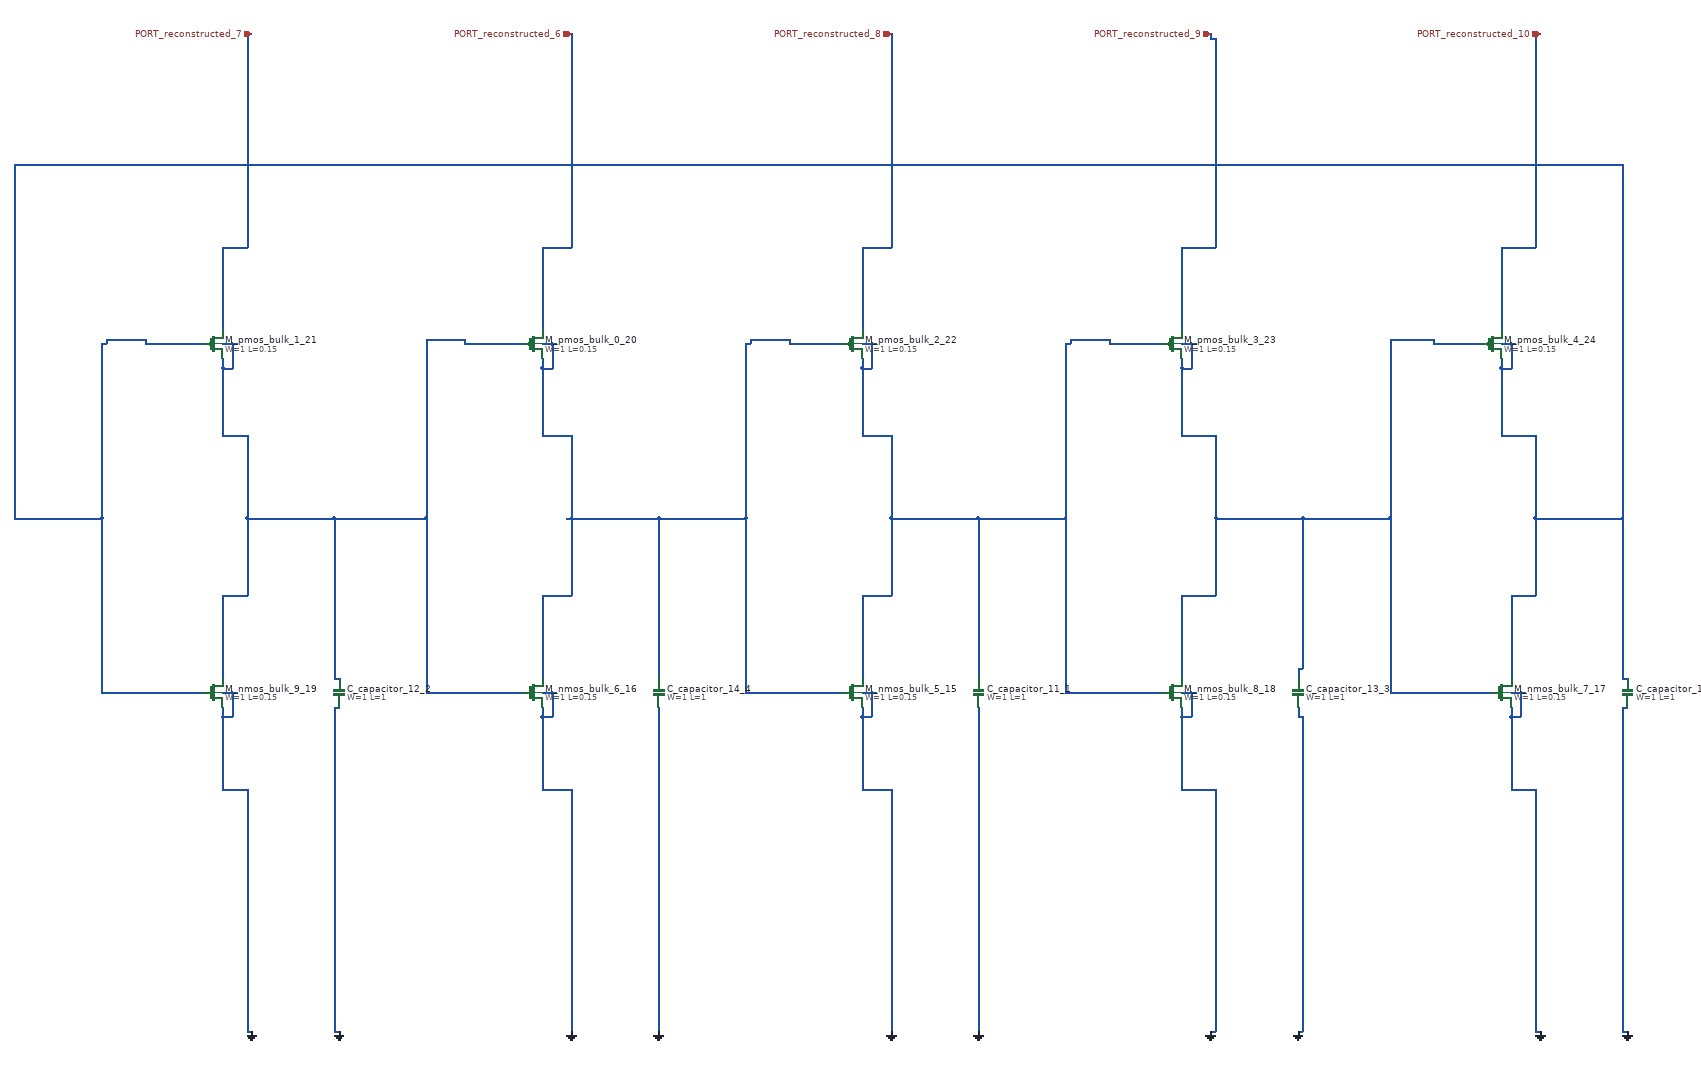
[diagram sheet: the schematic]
v {xschem version=3.4.8 file_version=1.2}
G {}
K {}
V {}
S {}
E {}
C {sky130_fd_pr/cap_mim_m3_1.sym} 3440 1560 0 0 {name="C_capacitor_10_0" model=cap_mim_m3_1 W=1 L=1 MF=1 spiceprefix=X}
C {sky130_fd_pr/cap_mim_m3_1.sym} 2100 1560 2 0 {name="C_capacitor_11_1" model=cap_mim_m3_1 W=1 L=1 MF=1 spiceprefix=X}
C {sky130_fd_pr/cap_mim_m3_1.sym} 780 1560 2 0 {name="C_capacitor_12_2" model=cap_mim_m3_1 W=1 L=1 MF=1 spiceprefix=X}
C {sky130_fd_pr/cap_mim_m3_1.sym} 2760 1560 2 0 {name="C_capacitor_13_3" model=cap_mim_m3_1 W=1 L=1 MF=1 spiceprefix=X}
C {sky130_fd_pr/cap_mim_m3_1.sym} 1440 1560 2 0 {name="C_capacitor_14_4" model=cap_mim_m3_1 W=1 L=1 MF=1 spiceprefix=X}
C {devices/gnd.sym} 3440 2260 0 0 {name="l_gnd_20_5" lab="GND"}
C {devices/gnd.sym} 2100 2260 0 0 {name="l_gnd_21_6" lab="GND"}
C {devices/gnd.sym} 2760 2260 0 0 {name="l_gnd_22_7" lab="GND"}
C {devices/gnd.sym} 1440 2260 0 0 {name="l_gnd_23_8" lab="GND"}
C {devices/gnd.sym} 780 2260 0 0 {name="l_gnd_24_9" lab="GND"}
C {devices/gnd.sym} 600 2260 0 0 {name="l_gnd_25_10" lab="GND"}
C {devices/gnd.sym} 3260 2260 0 0 {name="l_gnd_26_11" lab="GND"}
C {devices/gnd.sym} 2580 2260 0 0 {name="l_gnd_27_12" lab="GND"}
C {devices/gnd.sym} 1260 2260 0 0 {name="l_gnd_28_13" lab="GND"}
C {devices/gnd.sym} 1920 2260 0 0 {name="l_gnd_29_14" lab="GND"}
C {sky130_fd_pr/nfet_01v8.sym} 1840 1560 0 0 {name="M_nmos_bulk_5_15"
W=1
L=0.15
nf=1 
mult=1
ad="expr('int((@nf + 1)/2) * @W / @nf * 0.29')"
pd="expr('2*int((@nf + 1)/2) * (@W / @nf + 0.29)')"
as="expr('int((@nf + 2)/2) * @W / @nf * 0.29')"
ps="expr('2*int((@nf + 2)/2) * (@W / @nf + 0.29)')"
nrd="expr('0.29 / @W ')" nrs="expr('0.29 / @W ')"
sa=0 sb=0 sd=0
model=nfet_01v8
spiceprefix=X
}
C {sky130_fd_pr/nfet_01v8.sym} 1180 1560 0 0 {name="M_nmos_bulk_6_16"
W=1
L=0.15
nf=1 
mult=1
ad="expr('int((@nf + 1)/2) * @W / @nf * 0.29')"
pd="expr('2*int((@nf + 1)/2) * (@W / @nf + 0.29)')"
as="expr('int((@nf + 2)/2) * @W / @nf * 0.29')"
ps="expr('2*int((@nf + 2)/2) * (@W / @nf + 0.29)')"
nrd="expr('0.29 / @W ')" nrs="expr('0.29 / @W ')"
sa=0 sb=0 sd=0
model=nfet_01v8
spiceprefix=X
}
C {sky130_fd_pr/nfet_01v8.sym} 3180 1560 0 0 {name="M_nmos_bulk_7_17"
W=1
L=0.15
nf=1 
mult=1
ad="expr('int((@nf + 1)/2) * @W / @nf * 0.29')"
pd="expr('2*int((@nf + 1)/2) * (@W / @nf + 0.29)')"
as="expr('int((@nf + 2)/2) * @W / @nf * 0.29')"
ps="expr('2*int((@nf + 2)/2) * (@W / @nf + 0.29)')"
nrd="expr('0.29 / @W ')" nrs="expr('0.29 / @W ')"
sa=0 sb=0 sd=0
model=nfet_01v8
spiceprefix=X
}
C {sky130_fd_pr/nfet_01v8.sym} 2500 1560 0 0 {name="M_nmos_bulk_8_18"
W=1
L=0.15
nf=1 
mult=1
ad="expr('int((@nf + 1)/2) * @W / @nf * 0.29')"
pd="expr('2*int((@nf + 1)/2) * (@W / @nf + 0.29)')"
as="expr('int((@nf + 2)/2) * @W / @nf * 0.29')"
ps="expr('2*int((@nf + 2)/2) * (@W / @nf + 0.29)')"
nrd="expr('0.29 / @W ')" nrs="expr('0.29 / @W ')"
sa=0 sb=0 sd=0
model=nfet_01v8
spiceprefix=X
}
C {sky130_fd_pr/nfet_01v8.sym} 520 1560 0 0 {name="M_nmos_bulk_9_19"
W=1
L=0.15
nf=1 
mult=1
ad="expr('int((@nf + 1)/2) * @W / @nf * 0.29')"
pd="expr('2*int((@nf + 1)/2) * (@W / @nf + 0.29)')"
as="expr('int((@nf + 2)/2) * @W / @nf * 0.29')"
ps="expr('2*int((@nf + 2)/2) * (@W / @nf + 0.29)')"
nrd="expr('0.29 / @W ')" nrs="expr('0.29 / @W ')"
sa=0 sb=0 sd=0
model=nfet_01v8
spiceprefix=X
}
C {sky130_fd_pr/pfet_01v8.sym} 1180 840 0 0 {name="M_pmos_bulk_0_20"
W=1
L=0.15
nf=1
mult=1
ad="expr('int((@nf + 1)/2) * @W / @nf * 0.29')"
pd="expr('2*int((@nf + 1)/2) * (@W / @nf + 0.29)')"
as="expr('int((@nf + 2)/2) * @W / @nf * 0.29')"
ps="expr('2*int((@nf + 2)/2) * (@W / @nf + 0.29)')"
nrd="expr('0.29 / @W ')" nrs="expr('0.29 / @W ')"
sa=0 sb=0 sd=0
model=pfet_01v8
spiceprefix=X
}
C {sky130_fd_pr/pfet_01v8.sym} 520 840 0 0 {name="M_pmos_bulk_1_21"
W=1
L=0.15
nf=1
mult=1
ad="expr('int((@nf + 1)/2) * @W / @nf * 0.29')"
pd="expr('2*int((@nf + 1)/2) * (@W / @nf + 0.29)')"
as="expr('int((@nf + 2)/2) * @W / @nf * 0.29')"
ps="expr('2*int((@nf + 2)/2) * (@W / @nf + 0.29)')"
nrd="expr('0.29 / @W ')" nrs="expr('0.29 / @W ')"
sa=0 sb=0 sd=0
model=pfet_01v8
spiceprefix=X
}
C {sky130_fd_pr/pfet_01v8.sym} 1840 840 0 0 {name="M_pmos_bulk_2_22"
W=1
L=0.15
nf=1
mult=1
ad="expr('int((@nf + 1)/2) * @W / @nf * 0.29')"
pd="expr('2*int((@nf + 1)/2) * (@W / @nf + 0.29)')"
as="expr('int((@nf + 2)/2) * @W / @nf * 0.29')"
ps="expr('2*int((@nf + 2)/2) * (@W / @nf + 0.29)')"
nrd="expr('0.29 / @W ')" nrs="expr('0.29 / @W ')"
sa=0 sb=0 sd=0
model=pfet_01v8
spiceprefix=X
}
C {sky130_fd_pr/pfet_01v8.sym} 2500 840 0 0 {name="M_pmos_bulk_3_23"
W=1
L=0.15
nf=1
mult=1
ad="expr('int((@nf + 1)/2) * @W / @nf * 0.29')"
pd="expr('2*int((@nf + 1)/2) * (@W / @nf + 0.29)')"
as="expr('int((@nf + 2)/2) * @W / @nf * 0.29')"
ps="expr('2*int((@nf + 2)/2) * (@W / @nf + 0.29)')"
nrd="expr('0.29 / @W ')" nrs="expr('0.29 / @W ')"
sa=0 sb=0 sd=0
model=pfet_01v8
spiceprefix=X
}
C {sky130_fd_pr/pfet_01v8.sym} 3160 840 0 0 {name="M_pmos_bulk_4_24"
W=1
L=0.15
nf=1
mult=1
ad="expr('int((@nf + 1)/2) * @W / @nf * 0.29')"
pd="expr('2*int((@nf + 1)/2) * (@W / @nf + 0.29)')"
as="expr('int((@nf + 2)/2) * @W / @nf * 0.29')"
ps="expr('2*int((@nf + 2)/2) * (@W / @nf + 0.29)')"
nrd="expr('0.29 / @W ')" nrs="expr('0.29 / @W ')"
sa=0 sb=0 sd=0
model=pfet_01v8
spiceprefix=X
}
C {devices/ipin.sym} 3260 200 0 0 {name="p_port_15_25" lab="PORT_reconstructed_10"}
C {devices/ipin.sym} 2580 200 0 0 {name="p_port_16_26" lab="PORT_reconstructed_9"}
C {devices/ipin.sym} 1920 200 0 0 {name="p_port_17_27" lab="PORT_reconstructed_8"}
C {devices/ipin.sym} 1260 200 0 0 {name="p_port_18_28" lab="PORT_reconstructed_6"}
C {devices/ipin.sym} 600 200 0 0 {name="p_port_19_29" lab="PORT_reconstructed_7"}
N 590 2260 600 2260 {}
N 770 2260 780 2260 {}
N 2580 2260 2590 2260 {}
N 2760 2260 2770 2260 {}
N 3250 2260 3260 2260 {}
N 3430 2260 3440 2260 {}
N 540 1760 590 1760 {}
N 1200 1760 1260 1760 {}
N 1860 1760 1920 1760 {}
N 2520 1760 2590 1760 {}
N 3200 1760 3250 1760 {}
N 540 1610 560 1610 {}
N 1200 1610 1220 1610 {}
N 1860 1610 1880 1610 {}
N 2520 1610 2540 1610 {}
N 2760 1610 2770 1610 {}
N 3200 1610 3220 1610 {}
N 770 1590 780 1590 {}
N 3430 1590 3440 1590 {}
N 540 1560 560 1560 {}
N 560 1560 570 1560 {}
N 1200 1560 1220 1560 {}
N 1220 1560 1230 1560 {}
N 1860 1560 1880 1560 {}
N 1880 1560 1890 1560 {}
N 2520 1560 2540 1560 {}
N 2540 1560 2550 1560 {}
N 3200 1560 3220 1560 {}
N 3220 1560 3230 1560 {}
N 540 1760 540 1610 {}
N 540 1610 540 1590 {}
N 560 1610 560 1560 {}
N 590 2260 590 1760 {}
N 770 2260 770 1590 {}
N 1200 1760 1200 1610 {}
N 1200 1610 1200 1590 {}
N 1220 1610 1220 1560 {}
N 1260 2260 1260 1760 {}
N 1440 2260 1440 1590 {}
N 1860 1760 1860 1610 {}
N 1860 1610 1860 1590 {}
N 1880 1610 1880 1560 {}
N 1920 2260 1920 1760 {}
N 2100 2260 2100 1590 {}
N 2520 1760 2520 1610 {}
N 2520 1610 2520 1590 {}
N 2540 1610 2540 1560 {}
N 2590 2260 2590 1760 {}
N 2760 1610 2760 1590 {}
N 2770 2260 2770 1610 {}
N 3200 1760 3200 1610 {}
N 3200 1610 3200 1590 {}
N 3220 1610 3220 1560 {}
N 3250 2260 3250 1760 {}
N 3430 2260 3430 1590 {}
N 290 1560 500 1560 {}
N 3430 1530 3440 1530 {}
N 3200 1360 3250 1360 {}
N 110 1200 290 1200 {}
N 3250 1200 3430 1200 {}
N 3180 1030 3250 1030 {}
N 3180 890 3200 890 {}
N 290 840 300 840 {}
N 380 840 500 840 {}
N 3180 840 3200 840 {}
N 3200 840 3210 840 {}
N 300 830 380 830 {}
N 110 470 3430 470 {}
N 110 1200 110 470 {}
N 290 1560 290 1200 {}
N 290 1200 290 840 {}
N 300 840 300 830 {}
N 380 840 380 830 {}
N 3180 1030 3180 890 {}
N 3180 890 3180 870 {}
N 3200 1530 3200 1360 {}
N 3200 890 3200 840 {}
N 3250 1360 3250 1200 {}
N 3250 1200 3250 1030 {}
N 3430 1530 3430 1200 {}
N 3430 1200 3430 470 {}
N 3180 640 3250 640 {}
N 3250 200 3260 200 {}
N 3180 810 3180 640 {}
N 3250 640 3250 200 {}
N 2280 1560 2480 1560 {}
N 1860 1360 1920 1360 {}
N 1920 1200 2100 1200 {}
N 2100 1200 2280 1200 {}
N 1860 1030 1920 1030 {}
N 1860 890 1880 890 {}
N 1860 840 1880 840 {}
N 1880 840 1890 840 {}
N 2280 840 2290 840 {}
N 2370 840 2480 840 {}
N 2290 830 2370 830 {}
N 1860 1530 1860 1360 {}
N 1860 1030 1860 890 {}
N 1860 890 1860 870 {}
N 1880 890 1880 840 {}
N 1920 1360 1920 1200 {}
N 1920 1200 1920 1030 {}
N 2100 1530 2100 1200 {}
N 2280 1560 2280 1200 {}
N 2280 1200 2280 840 {}
N 2290 840 2290 830 {}
N 2370 840 2370 830 {}
N 1620 1560 1820 1560 {}
N 1200 1360 1260 1360 {}
N 1250 1200 1260 1200 {}
N 1260 1200 1440 1200 {}
N 1440 1200 1620 1200 {}
N 1200 1030 1260 1030 {}
N 1200 890 1220 890 {}
N 1200 840 1220 840 {}
N 1220 840 1230 840 {}
N 1620 840 1630 840 {}
N 1710 840 1820 840 {}
N 1630 830 1710 830 {}
N 1200 1530 1200 1360 {}
N 1200 1030 1200 890 {}
N 1200 890 1200 870 {}
N 1220 890 1220 840 {}
N 1260 1360 1260 1200 {}
N 1260 1200 1260 1030 {}
N 1440 1530 1440 1200 {}
N 1620 1560 1620 1200 {}
N 1620 1200 1620 840 {}
N 1630 840 1630 830 {}
N 1710 840 1710 830 {}
N 960 1560 1160 1560 {}
N 770 1530 780 1530 {}
N 540 1360 590 1360 {}
N 590 1200 770 1200 {}
N 770 1200 960 1200 {}
N 540 1030 590 1030 {}
N 540 890 560 890 {}
N 540 840 560 840 {}
N 560 840 570 840 {}
N 1040 840 1160 840 {}
N 960 830 1040 830 {}
N 540 1530 540 1360 {}
N 540 1030 540 890 {}
N 540 890 540 870 {}
N 560 890 560 840 {}
N 590 1360 590 1200 {}
N 590 1200 590 1030 {}
N 770 1530 770 1200 {}
N 960 1560 960 1200 {}
N 960 1200 960 830 {}
N 1040 840 1040 830 {}
N 2950 1560 3160 1560 {}
N 2760 1510 2770 1510 {}
N 2520 1360 2590 1360 {}
N 2590 1200 2770 1200 {}
N 2770 1200 2950 1200 {}
N 2520 1030 2590 1030 {}
N 2520 890 2540 890 {}
N 2520 840 2540 840 {}
N 2540 840 2550 840 {}
N 3040 840 3140 840 {}
N 2950 830 3040 830 {}
N 2520 1530 2520 1360 {}
N 2520 1030 2520 890 {}
N 2520 890 2520 870 {}
N 2540 890 2540 840 {}
N 2590 1360 2590 1200 {}
N 2590 1200 2590 1030 {}
N 2760 1530 2760 1510 {}
N 2770 1510 2770 1200 {}
N 2950 1560 2950 1200 {}
N 2950 1200 2950 830 {}
N 3040 840 3040 830 {}
N 1200 640 1260 640 {}
N 1200 810 1200 640 {}
N 1260 640 1260 200 {}
N 540 640 590 640 {}
N 590 200 600 200 {}
N 540 810 540 640 {}
N 590 640 590 200 {}
N 1860 640 1920 640 {}
N 1860 810 1860 640 {}
N 1920 640 1920 200 {}
N 2520 640 2590 640 {}
N 2580 210 2590 210 {}
N 2520 810 2520 640 {}
N 2580 210 2580 200 {}
N 2590 640 2590 210 {}
